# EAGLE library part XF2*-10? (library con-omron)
OMRON FPC Connector Source : http://www.omron.com/ecb/products/pdf/fpc.pdf

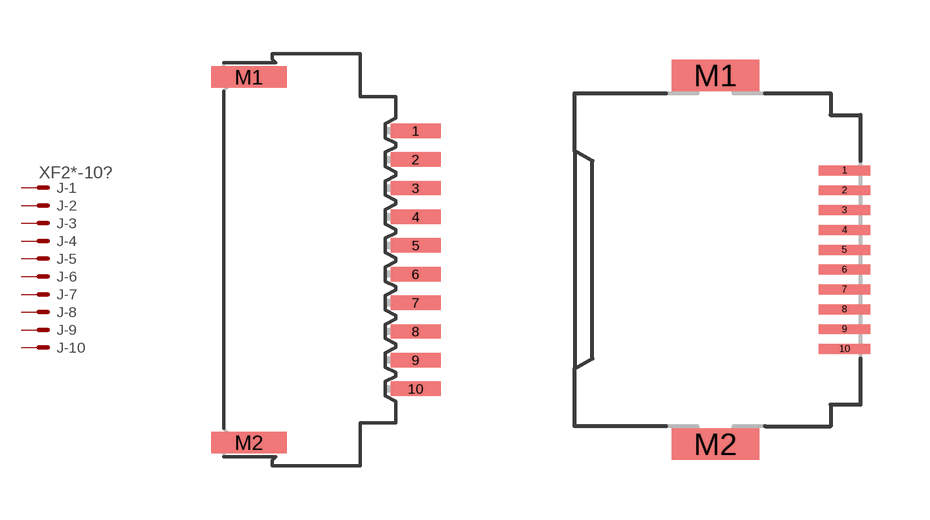
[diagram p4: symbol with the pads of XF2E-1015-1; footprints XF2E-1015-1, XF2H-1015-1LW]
Designator prefix J; gates -1=PV -2=P -3=P -4=P -5=P -6=P -7=P -8=P -9=P -10=P

## XF2E-1015-1  [XF2E-1015-1]
1  -1:MSV  pas
2  -2:MS  pas
3  -3:MS  pas
4  -4:MS  pas
5  -5:MS  pas
6  -6:MS  pas
7  -7:MS  pas
8  -8:MS  pas
9  -9:MS  pas
10  -10:MS  pas

## XF2H-1015-1LW  [XF2H-1015-1LW]
Pads as for XF2E-1015-1

## XF2J-1024-11  [XF2J-1024-11]
Pads as for XF2E-1015-1

## XF2J-1024-12  [XF2J-1024-12]
Pads as for XF2E-1015-1

## XF2L-1025-1  [XF2L-1025-1]
Pads as for XF2E-1015-1

## XF2L-1035-1  [XF2L-1035-1]
Pads as for XF2E-1015-1

## Footprint XF2E-1015-1 (pad centres in mm)
Non-ZIF Type (0.8 mm-pitch) Source : http://www.omron.com/ecb/products/pdf/fpc.pdf
smd 1.4 x 0.4: 1 2.54,3.6; 2 2.54,2.8; 3 2.54,2; 4 2.54,1.2; 5 2.54,0.4; 6 2.54,-0.4; 7 2.54,-1.2; 8 2.54,-2; 9 2.54,-2.8; 10 2.54,-3.6
smd 2.1 x 0.6: M1 -2.11,5.1; M2 -2.11,-5.1

## Footprint XF2H-1015-1LW (pad centres in mm)
Standard Rotary Backlock Type (0.5 mm-pitch) Source : http://www.omron.com/ecb/products/pdf/fpc.pdf
smd 1.3 x 0.25: 1 3.175,2.25; 2 3.175,1.75; 3 3.175,1.25; 4 3.175,0.75; 5 3.175,0.25; 6 3.175,-0.25; 7 3.175,-0.75; 8 3.175,-1.25; 9 3.175,-1.75; 10 3.175,-2.25
smd 2.2 x 0.8: M1 -0.075,4.65; M2 -0.075,-4.65

## Footprint XF2J-1024-11 (pad centres in mm)
ZIF Slide-locking Type (0.5 mm-pitch) Standard Source : http://www.omron.com/ecb/products/pdf/fpc.pdf
smd 1.6 x 0.5: 1 1.2,2.25; 2 -1.2,1.75; 3 1.2,1.25; 4 -1.2,0.75; 5 1.2,0.25; 6 -1.2,-0.25; 7 1.2,-0.75; 8 -1.2,-1.25; 9 1.2,-1.75; 10 -1.2,-2.25
smd 2.9 x 1.4: M1 0,3.95; M2 0,-3.95

## Footprint XF2J-1024-12 (pad centres in mm)
ZIF Slide-locking Type (0.5 mm-pitch) Reverse Source : http://www.omron.com/ecb/products/pdf/fpc.pdf
smd 1.6 x 0.5: 1 -1.2,2.25; 2 1.2,1.75; 3 -1.2,1.25; 4 1.2,0.75; 5 -1.2,0.25; 6 1.2,-0.25; 7 -1.2,-0.75; 8 1.2,-1.25; 9 -1.2,-1.75; 10 1.2,-2.25
smd 2.9 x 1.4: M1 0,3.95; M2 0,-3.95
